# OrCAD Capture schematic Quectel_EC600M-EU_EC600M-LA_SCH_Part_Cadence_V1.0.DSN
size A2

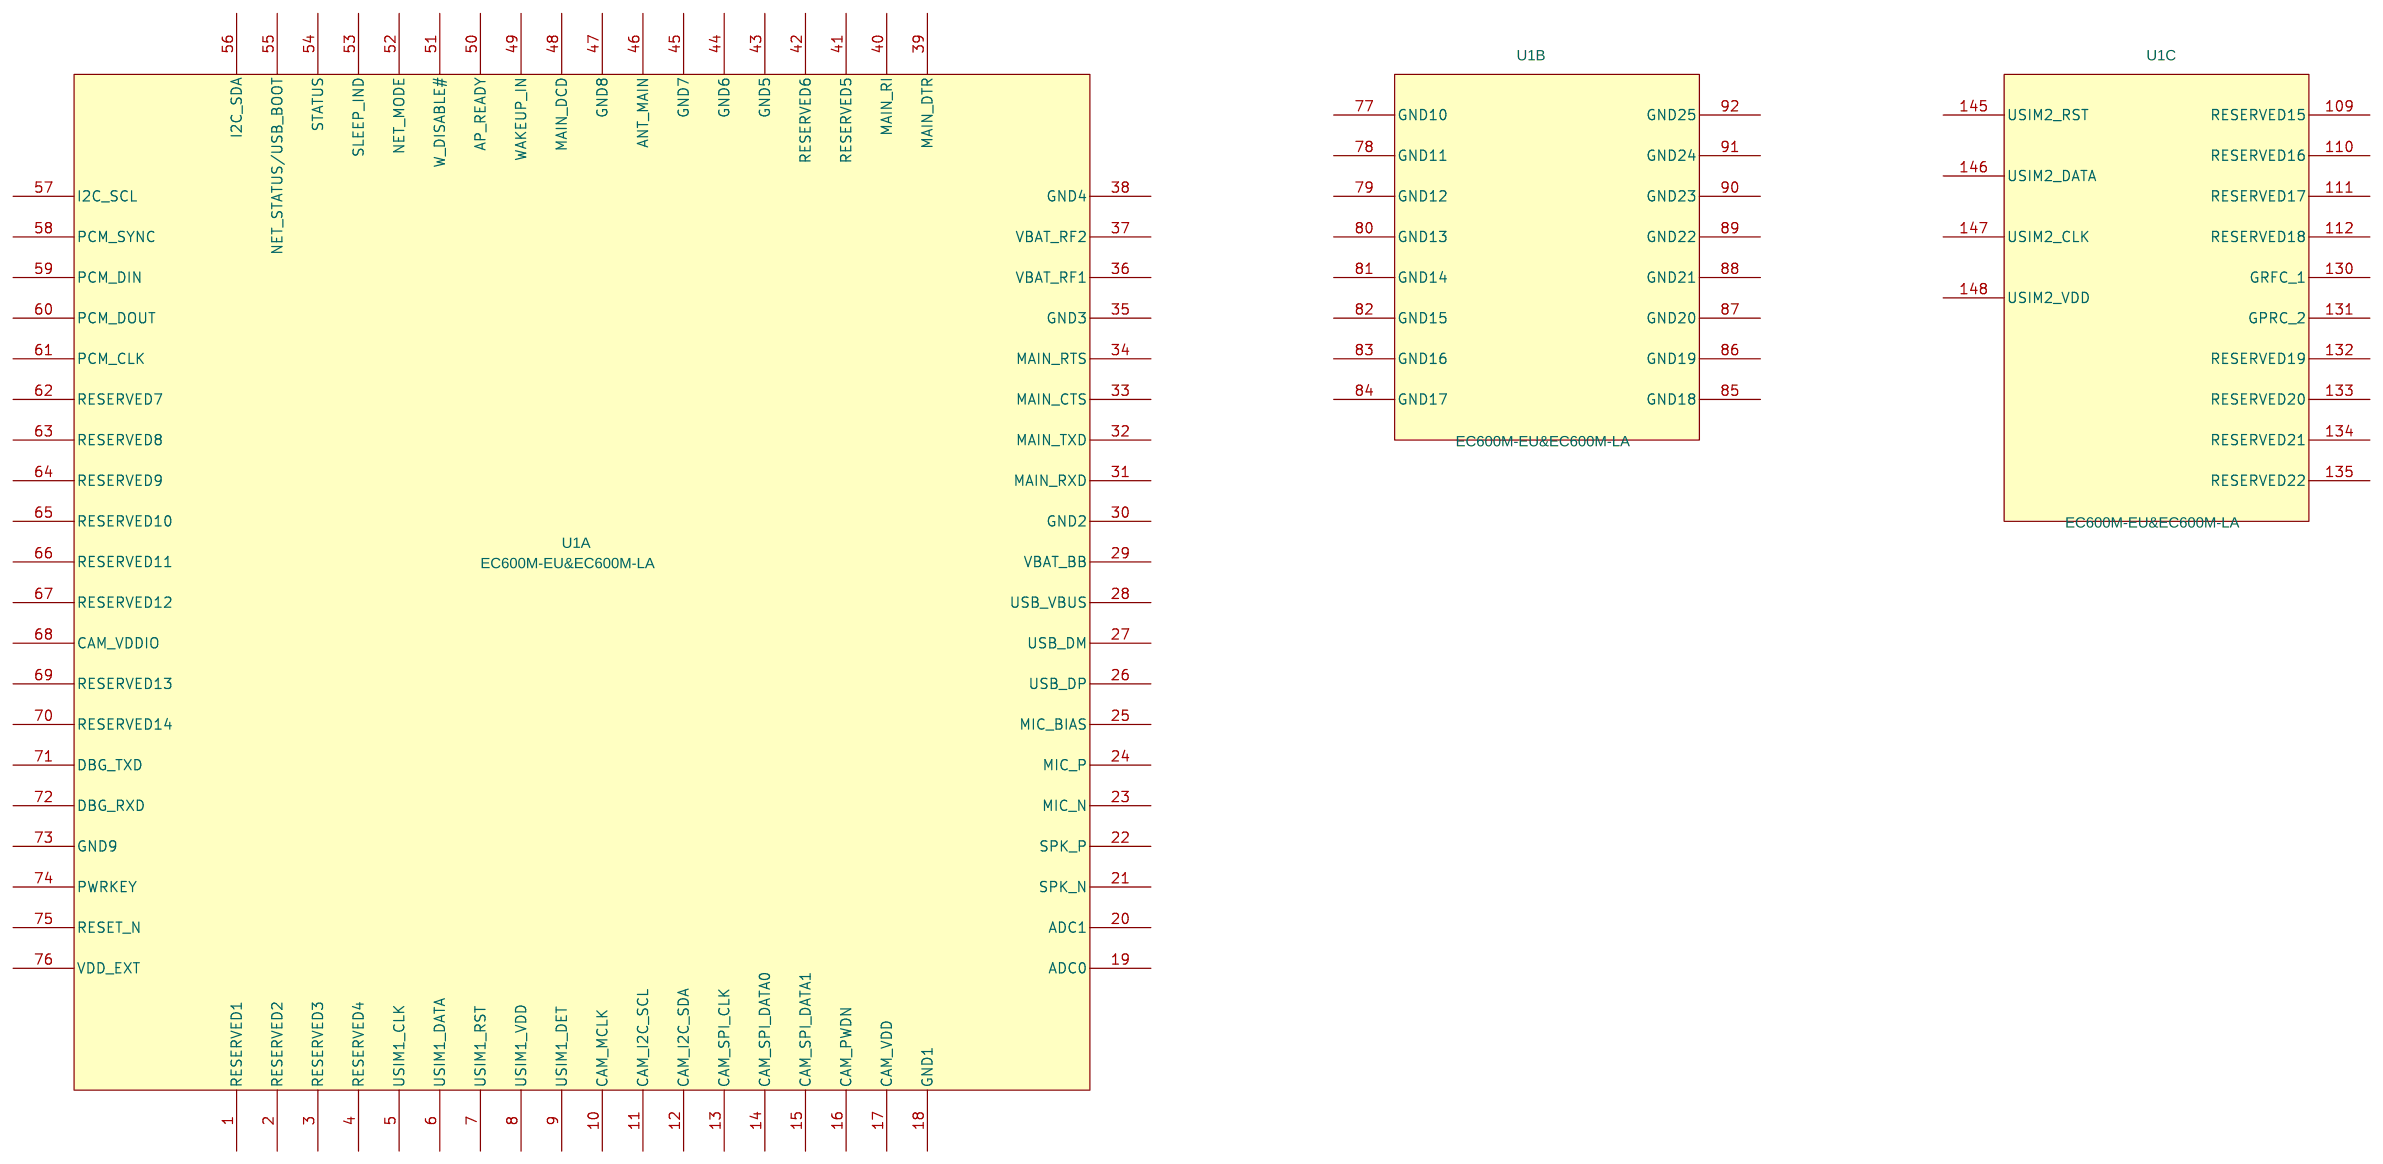
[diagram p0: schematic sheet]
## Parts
U1  EC600M-EU&EC600M-LA  [EC600M-EU_EC600M-LA]  (sections A,B,C)

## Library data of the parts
U1 = EC600M-EU_EC600M-LA

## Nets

Not connected (* = marked no-connect by the designer): U1 1(RESERVED1) 2(RESERVED2) 3(RESERVED3) 4(RESERVED4) 5(USIM1_CLK) 6(USIM1_DATA) 7(USIM1_RST) 8(USIM1_VDD) 9(USIM1_DET) 10(CAM_MCLK) 11(CAM_I2C_SCL) 12(CAM_I2C_SDA) 13(CAM_SPI_CLK) 14(CAM_SPI_DATA0) 15(CAM_SPI_DATA1) 16(CAM_PWDN) 17(CAM_VDD) 18(GND1) 19(ADC0) 20(ADC1) 21(SPK_N) 22(SPK_P) 23(MIC_N) 24(MIC_P) 25(MIC_BIAS) 26(USB_DP) 27(USB_DM) 28(USB_VBUS) 29(VBAT_BB) 30(GND2) 31(MAIN_RXD) 32(MAIN_TXD) 33(MAIN_CTS) 34(MAIN_RTS) 35(GND3) 36(VBAT_RF1) 37(VBAT_RF2) 38(GND4) 39(MAIN_DTR) 40(MAIN_RI) 41(RESERVED5) 42(RESERVED6) 43(GND5) 44(GND6) 45(GND7) 46(ANT_MAIN) 47(GND8) 48(MAIN_DCD) 49(WAKEUP_IN) 50(AP_READY) 51(W_DISABLE#) 52(NET_MODE) 53(SLEEP_IND) 54(STATUS) 55(NET_STATUS/USB_BOOT) 56(I2C_SDA) 57(I2C_SCL) 58(PCM_SYNC) 59(PCM_DIN) 60(PCM_DOUT) 61(PCM_CLK) 62(RESERVED7) 63(RESERVED8) 64(RESERVED9) 65(RESERVED10) 66(RESERVED11) 67(RESERVED12) 68(CAM_VDDIO) 69(RESERVED13) 70(RESERVED14) 71(DBG_TXD) 72(DBG_RXD) 73(GND9) 74(PWRKEY) 75(RESET_N) 76(VDD_EXT) 77(GND10) 78(GND11) 79(GND12) 80(GND13) 81(GND14) 82(GND15) 83(GND16) 84(GND17) 85(GND18) 86(GND19) 87(GND20) 88(GND21) 89(GND22) 90(GND23) 91(GND24) 92(GND25) 109(RESERVED15) 110(RESERVED16) 111(RESERVED17) 112(RESERVED18) 130(GRFC_1) 131(GPRC_2) 132(RESERVED19) 133(RESERVED20) 134(RESERVED21) 135(RESERVED22) 145(USIM2_RST) 146(USIM2_DATA) 147(USIM2_CLK) 148(USIM2_VDD)
